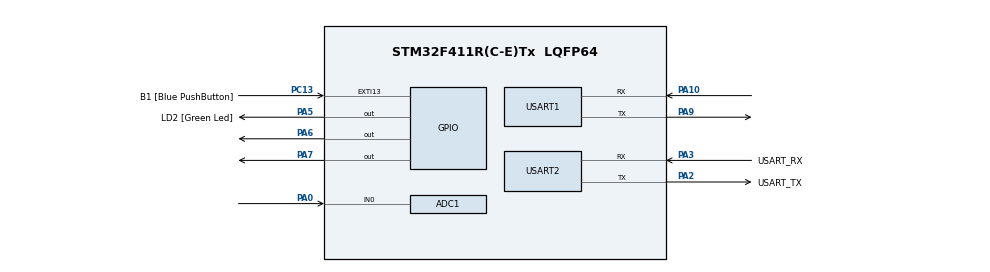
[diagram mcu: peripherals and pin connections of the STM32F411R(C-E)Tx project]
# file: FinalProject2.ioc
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ADC1.Channel-1\#ChannelRegularConversion=ADC_CHANNEL_0
ADC1.NbrOfConversionFlag=1
ADC1.Rank-1\#ChannelRegularConversion=1
ADC1.SamplingTime-1\#ChannelRegularConversion=ADC_SAMPLETIME_3CYCLES
ADC1.master=1
Mcu.Family=STM32F4
Mcu.Name=STM32F411R(C-E)Tx
Mcu.Package=LQFP64
NVIC.PriorityGroup=NVIC_PRIORITYGROUP_0
NVIC.TIM2_IRQn=true\:0\:0\:false\:false\:true\:true\:true\:true
PA0-WKUP.Signal=ADCx_IN0
PA10.Mode=Asynchronous
PA10.Signal=USART1_RX
PA13.GPIO_Label=TMS
PA13.Mode=Serial_Wire
PA13.Signal=SYS_JTMS-SWDIO
PA14.GPIO_Label=TCK
PA14.Mode=Serial_Wire
PA14.Signal=SYS_JTCK-SWCLK
PA2.GPIO_Label=USART_TX
PA2.Mode=Asynchronous
PA2.Signal=USART2_TX
PA3.GPIO_Label=USART_RX
PA3.Mode=Asynchronous
PA3.Signal=USART2_RX
PA5.GPIO_Label=LD2 [Green Led]
PA5.Signal=GPIO_Output
PA6.Signal=GPIO_Output
PA7.Signal=GPIO_Output
PA9.Mode=Asynchronous
PA9.Signal=USART1_TX
PB3.GPIO_Label=SWO
PB3.Signal=SYS_JTDO-SWO
PC13-ANTI_TAMP.GPIO_Label=B1 [Blue PushButton]
PC13-ANTI_TAMP.GPIO_ModeDefaultEXTI=GPIO_MODE_IT_FALLING
PC13-ANTI_TAMP.Signal=GPXTI13
PC14-OSC32_IN.Mode=LSE-External-Oscillator
PC14-OSC32_IN.Signal=RCC_OSC32_IN
PC15-OSC32_OUT.Mode=LSE-External-Oscillator
PC15-OSC32_OUT.Signal=RCC_OSC32_OUT
PH0\ -\ OSC_IN.Mode=HSE-External-Clock-Source
PH0\ -\ OSC_IN.Signal=RCC_OSC_IN
PH1\ -\ OSC_OUT.Mode=HSE-External-Clock-Source
PH1\ -\ OSC_OUT.Signal=RCC_OSC_OUT
ProjectManager.HeapSize=0x200
ProjectManager.StackSize=0x400
ProjectManager.TargetToolchain=STM32CubeIDE
RCC.48MHZClocksFreq_Value=84000000
RCC.AHBFreq_Value=84000000
RCC.APB1CLKDivider=RCC_HCLK_DIV2
RCC.APB1Freq_Value=42000000
RCC.APB1TimFreq_Value=84000000
RCC.APB2Freq_Value=84000000
RCC.APB2TimFreq_Value=84000000
RCC.CortexFreq_Value=84000000
RCC.FLatency-AdvancedSettings=FLASH_LATENCY_2
RCC.HCLKFreq_Value=84000000
RCC.HSE_VALUE=8000000
RCC.HSI_VALUE=16000000
RCC.PLLN=336
RCC.PLLP=RCC_PLLP_DIV4
RCC.SYSCLKFreq_VALUE=84000000
RCC.SYSCLKSource=RCC_SYSCLKSOURCE_PLLCLK
RCC.VCOOutputFreq_Value=336000000
SH.ADCx_IN0.0=ADC1_IN0,IN0
TIM2.Period=10000
TIM2.Prescaler=100
USART1.VirtualMode=VM_ASYNC
USART2.VirtualMode=VM_ASYNC
VP_TIM2_VS_ClockSourceINT.Mode=Internal
board=NUCLEO-F411RE

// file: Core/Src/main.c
/* USER CODE BEGIN Header */
/**
  ******************************************************************************
  * @file           : main.c
  * @brief          : Main program body
  ******************************************************************************
  * @attention
  *
  * Copyright (c) 2023 STMicroelectronics.
  * All rights reserved.
  *
  * This software is licensed under terms that can be found in the LICENSE file
  * in the root directory of this software component.
  * If no LICENSE file comes with this software, it is provided AS-IS.
  *
  ******************************************************************************
  */
/* USER CODE END Header */
#include "main.h"

ADC_HandleTypeDef hadc1;

TIM_HandleTypeDef htim2;

UART_HandleTypeDef huart1;
UART_HandleTypeDef huart2;

void SystemClock_Config(void);
static void MX_GPIO_Init(void);
static void MX_USART2_UART_Init(void);
static void MX_USART1_UART_Init(void);
static void MX_ADC1_Init(void);
static void MX_TIM2_Init(void);

/* USER CODE BEGIN 0 */
int workingInProgress = 0,dataPrepared = 0,currentPositionOfBuffer = 0;
uint8_t buffer[20];
ADC_ChannelConfTypeDef sConfig = {0};
void HAL_GPIO_EXTI_Callback(uint16_t GPIO_Pin){
	 if(GPIO_Pin != GPIO_PIN_13)
		 return ;
	 if(workingInProgress)
		 return ;
	 dataPrepared = 0;
	 workingInProgress = 1;
	 HAL_GPIO_WritePin(GPIOA, GPIO_PIN_5, GPIO_PIN_RESET);
	 HAL_GPIO_WritePin(GPIOA, GPIO_PIN_7, GPIO_PIN_SET);
	 HAL_GPIO_WritePin(GPIOC, GPIO_PIN_7, GPIO_PIN_SET);

	 // get Value from TDS Sensor
	 int TDSav = 0;
	 sConfig.Channel = ADC_CHANNEL_0;
	 for(int i=1;i<=100;i++){
		 HAL_ADC_ConfigChannel(&hadc1, &sConfig);
		 HAL_ADC_Start(&hadc1);
		 int adcValue;
		 if(HAL_ADC_PollForConversion(&hadc1, 100) == HAL_OK){
			adcValue = HAL_ADC_GetValue(&hadc1);
			TDSav+=adcValue;
		 }
	 }
	 TDSav/=100;

	 // get Value from thermo Sensor
	 int thermoAv = 0;
	 sConfig.Channel = ADC_CHANNEL_1;
	 for(int i=1;i<=100;i++){
		 HAL_ADC_ConfigChannel(&hadc1, &sConfig);
		 HAL_ADC_Start(&hadc1);
		 int adcValue;
		 if(HAL_ADC_PollForConversion(&hadc1, 100) == HAL_OK){
			adcValue = HAL_ADC_GetValue(&hadc1);
			thermoAv+=adcValue;
		 }
	 }
	 thermoAv/=100;

	 // get Value from O2 Sensor
	 int O2av = 0;
	 sConfig.Channel = ADC_CHANNEL_2;
	 for(int i=1;i<=100;i++){
		 HAL_ADC_ConfigChannel(&hadc1, &sConfig);
		 HAL_ADC_Start(&hadc1);
		 int adcValue;
		 if(HAL_ADC_PollForConversion(&hadc1, 100) == HAL_OK){
			adcValue = HAL_ADC_GetValue(&hadc1);
			O2av+=adcValue;
		 }
	 }
	 O2av/=100;

	 // Convert Int to String
	 sprintf(buffer, "%04d", TDSav);
	 sprintf(buffer+4, "%04d", thermoAv);
	 sprintf(buffer+8, "%04d", O2av);
	 buffer[0] = 'A';
	 buffer[4] = 'B';
	 buffer[8] = 'C';
	 buffer[12] = '\0';

	 currentPositionOfBuffer = 0;
	 dataPrepared = 1;
}

void HAL_TIM_PeriodElapsedCallback(TIM_HandleTypeDef* htim){
	if(!dataPrepared)
		return ;

	// TIM1 is used for display through UART
	if(htim->Instance == TIM2){
		// Display the counter values via UART
		if(currentPositionOfBuffer == 12){
			HAL_UART_Transmit(&huart2, "\n\r", 2, 100);
			dataPrepared = 0;
			workingInProgress = 0;
			return ;
		}
//		HAL_UART_Transmit(&huart1, &buffer[currentPositionOfBuffer++], 1, 100);
		HAL_UART_Transmit(&huart2, &buffer[currentPositionOfBuffer++], 1, 100);
	}
}
/* USER CODE END 0 */

int main(void)
{

  /* MCU Configuration--------------------------------------------------------*/

  /* Reset of all peripherals, Initializes the Flash interface and the Systick. */
  HAL_Init();

  /* Configure the system clock */
  SystemClock_Config();

  /* Initialize all configured peripherals */
  MX_GPIO_Init();
  MX_USART2_UART_Init();
  MX_USART1_UART_Init();
  MX_ADC1_Init();
  MX_TIM2_Init();
  /* USER CODE BEGIN 2 */
  HAL_TIM_Base_Start_IT(&htim2);
  /* USER CODE END 2 */

  /* Infinite loop */
  /* USER CODE BEGIN WHILE */
  sConfig.Channel = ADC_CHANNEL_0;
  sConfig.Rank = 1;
  sConfig.SamplingTime = ADC_SAMPLETIME_3CYCLES;
  int pressing = 0;
  HAL_UART_Transmit(&huart2, "Initialize successful\n\r", 23, HAL_MAX_DELAY);
  while (1)
  {
	 int pressedButton = !HAL_GPIO_ReadPin(GPIOC, GPIO_PIN_13);
	 HAL_GPIO_WritePin(GPIOA, GPIO_PIN_5, !workingInProgress);
	 HAL_GPIO_WritePin(GPIOA, GPIO_PIN_7, workingInProgress);
	 HAL_GPIO_WritePin(GPIOC, GPIO_PIN_7, workingInProgress);
    /* USER CODE END WHILE */

  }
}

void SystemClock_Config(void)
{
  RCC_OscInitTypeDef RCC_OscInitStruct = {0};
  RCC_ClkInitTypeDef RCC_ClkInitStruct = {0};

  /** Configure the main internal regulator output voltage
  */
  __HAL_RCC_PWR_CLK_ENABLE();
  __HAL_PWR_VOLTAGESCALING_CONFIG(PWR_REGULATOR_VOLTAGE_SCALE1);

  /** Initializes the RCC Oscillators according to the specified parameters
  * in the RCC_OscInitTypeDef structure.
  */
  RCC_OscInitStruct.OscillatorType = RCC_OSCILLATORTYPE_HSI;
  RCC_OscInitStruct.HSIState = RCC_HSI_ON;
  RCC_OscInitStruct.HSICalibrationValue = RCC_HSICALIBRATION_DEFAULT;
  RCC_OscInitStruct.PLL.PLLState = RCC_PLL_ON;
  RCC_OscInitStruct.PLL.PLLSource = RCC_PLLSOURCE_HSI;
  RCC_OscInitStruct.PLL.PLLM = 8;
  RCC_OscInitStruct.PLL.PLLN = 100;
  RCC_OscInitStruct.PLL.PLLP = RCC_PLLP_DIV2;
  RCC_OscInitStruct.PLL.PLLQ = 4;
  if (HAL_RCC_OscConfig(&RCC_OscInitStruct) != HAL_OK)
  {
    Error_Handler();
  }

  /** Initializes the CPU, AHB and APB buses clocks
  */
  RCC_ClkInitStruct.ClockType = RCC_CLOCKTYPE_HCLK|RCC_CLOCKTYPE_SYSCLK
                              |RCC_CLOCKTYPE_PCLK1|RCC_CLOCKTYPE_PCLK2;
  RCC_ClkInitStruct.SYSCLKSource = RCC_SYSCLKSOURCE_PLLCLK;
  RCC_ClkInitStruct.AHBCLKDivider = RCC_SYSCLK_DIV1;
  RCC_ClkInitStruct.APB1CLKDivider = RCC_HCLK_DIV2;
  RCC_ClkInitStruct.APB2CLKDivider = RCC_HCLK_DIV1;

  if (HAL_RCC_ClockConfig(&RCC_ClkInitStruct, FLASH_LATENCY_3) != HAL_OK)
  {
    Error_Handler();
  }
}

static void MX_ADC1_Init(void)
{

  ADC_ChannelConfTypeDef sConfig = {0};

  /** Configure the global features of the ADC (Clock, Resolution, Data Alignment and number of conversion)
  */
  hadc1.Instance = ADC1;
  hadc1.Init.ClockPrescaler = ADC_CLOCK_SYNC_PCLK_DIV4;
  hadc1.Init.Resolution = ADC_RESOLUTION_12B;
  hadc1.Init.ScanConvMode = ENABLE;
  hadc1.Init.ContinuousConvMode = DISABLE;
  hadc1.Init.DiscontinuousConvMode = DISABLE;
  hadc1.Init.ExternalTrigConvEdge = ADC_EXTERNALTRIGCONVEDGE_NONE;
  hadc1.Init.ExternalTrigConv = ADC_SOFTWARE_START;
  hadc1.Init.DataAlign = ADC_DATAALIGN_RIGHT;
  hadc1.Init.NbrOfConversion = 3;
  hadc1.Init.DMAContinuousRequests = DISABLE;
  hadc1.Init.EOCSelection = ADC_EOC_SINGLE_CONV;
  if (HAL_ADC_Init(&hadc1) != HAL_OK)
  {
    Error_Handler();
  }

  /** Configure for the selected ADC regular channel its corresponding rank in the sequencer and its sample time.
  */
  sConfig.Channel = ADC_CHANNEL_0;
  sConfig.Rank = 1;
  sConfig.SamplingTime = ADC_SAMPLETIME_3CYCLES;
  if (HAL_ADC_ConfigChannel(&hadc1, &sConfig) != HAL_OK)
  {
    Error_Handler();
  }

  /** Configure for the selected ADC regular channel its corresponding rank in the sequencer and its sample time.
  */
  sConfig.Rank = 2;
  if (HAL_ADC_ConfigChannel(&hadc1, &sConfig) != HAL_OK)
  {
    Error_Handler();
  }

  /** Configure for the selected ADC regular channel its corresponding rank in the sequencer and its sample time.
  */
  sConfig.Rank = 3;
  if (HAL_ADC_ConfigChannel(&hadc1, &sConfig) != HAL_OK)
  {
    Error_Handler();
  }

}

static void MX_TIM2_Init(void)
{

  TIM_ClockConfigTypeDef sClockSourceConfig = {0};
  TIM_MasterConfigTypeDef sMasterConfig = {0};

  htim2.Instance = TIM2;
  htim2.Init.Prescaler = 100;
  htim2.Init.CounterMode = TIM_COUNTERMODE_UP;
  htim2.Init.Period = 100000;
  htim2.Init.ClockDivision = TIM_CLOCKDIVISION_DIV1;
  htim2.Init.AutoReloadPreload = TIM_AUTORELOAD_PRELOAD_DISABLE;
  if (HAL_TIM_Base_Init(&htim2) != HAL_OK)
  {
    Error_Handler();
  }
  sClockSourceConfig.ClockSource = TIM_CLOCKSOURCE_INTERNAL;
  if (HAL_TIM_ConfigClockSource(&htim2, &sClockSourceConfig) != HAL_OK)
  {
    Error_Handler();
  }
  sMasterConfig.MasterOutputTrigger = TIM_TRGO_RESET;
  sMasterConfig.MasterSlaveMode = TIM_MASTERSLAVEMODE_DISABLE;
  if (HAL_TIMEx_MasterConfigSynchronization(&htim2, &sMasterConfig) != HAL_OK)
  {
    Error_Handler();
  }

}

static void MX_USART1_UART_Init(void)
{

  huart1.Instance = USART1;
  huart1.Init.BaudRate = 115200;
  huart1.Init.WordLength = UART_WORDLENGTH_8B;
  huart1.Init.StopBits = UART_STOPBITS_1;
  huart1.Init.Parity = UART_PARITY_NONE;
  huart1.Init.Mode = UART_MODE_TX_RX;
  huart1.Init.HwFlowCtl = UART_HWCONTROL_NONE;
  huart1.Init.OverSampling = UART_OVERSAMPLING_16;
  if (HAL_UART_Init(&huart1) != HAL_OK)
  {
    Error_Handler();
  }

}

static void MX_USART2_UART_Init(void)
{

  huart2.Instance = USART2;
  huart2.Init.BaudRate = 115200;
  huart2.Init.WordLength = UART_WORDLENGTH_8B;
  huart2.Init.StopBits = UART_STOPBITS_1;
  huart2.Init.Parity = UART_PARITY_NONE;
  huart2.Init.Mode = UART_MODE_TX_RX;
  huart2.Init.HwFlowCtl = UART_HWCONTROL_NONE;
  huart2.Init.OverSampling = UART_OVERSAMPLING_16;
  if (HAL_UART_Init(&huart2) != HAL_OK)
  {
    Error_Handler();
  }

}

static void MX_GPIO_Init(void)
{
  GPIO_InitTypeDef GPIO_InitStruct = {0};

  /* GPIO Ports Clock Enable */
  __HAL_RCC_GPIOC_CLK_ENABLE();
  __HAL_RCC_GPIOH_CLK_ENABLE();
  __HAL_RCC_GPIOA_CLK_ENABLE();
  __HAL_RCC_GPIOB_CLK_ENABLE();

  /*Configure GPIO pin Output Level */
  HAL_GPIO_WritePin(GPIOA, LD2_Pin|GPIO_PIN_6|GPIO_PIN_7, GPIO_PIN_RESET);

  /*Configure GPIO pin Output Level */
  HAL_GPIO_WritePin(GPIOC, GPIO_PIN_7, GPIO_PIN_RESET);

  /*Configure GPIO pin : B1_Pin */
  GPIO_InitStruct.Pin = B1_Pin;
  GPIO_InitStruct.Mode = GPIO_MODE_IT_FALLING;
  GPIO_InitStruct.Pull = GPIO_NOPULL;
  HAL_GPIO_Init(B1_GPIO_Port, &GPIO_InitStruct);

  /*Configure GPIO pins : LD2_Pin PA6 PA7 */
  GPIO_InitStruct.Pin = LD2_Pin|GPIO_PIN_6|GPIO_PIN_7;
  GPIO_InitStruct.Mode = GPIO_MODE_OUTPUT_PP;
  GPIO_InitStruct.Pull = GPIO_NOPULL;
  GPIO_InitStruct.Speed = GPIO_SPEED_FREQ_LOW;
  HAL_GPIO_Init(GPIOA, &GPIO_InitStruct);

  /*Configure GPIO pin : PC7 */
  GPIO_InitStruct.Pin = GPIO_PIN_7;
  GPIO_InitStruct.Mode = GPIO_MODE_OUTPUT_PP;
  GPIO_InitStruct.Pull = GPIO_NOPULL;
  GPIO_InitStruct.Speed = GPIO_SPEED_FREQ_LOW;
  HAL_GPIO_Init(GPIOC, &GPIO_InitStruct);

  /* EXTI interrupt init*/
  HAL_NVIC_SetPriority(EXTI15_10_IRQn, 0, 0);
  HAL_NVIC_EnableIRQ(EXTI15_10_IRQn);

}

void Error_Handler(void)
{
  __disable_irq();
  while (1)
  {
  }
}
